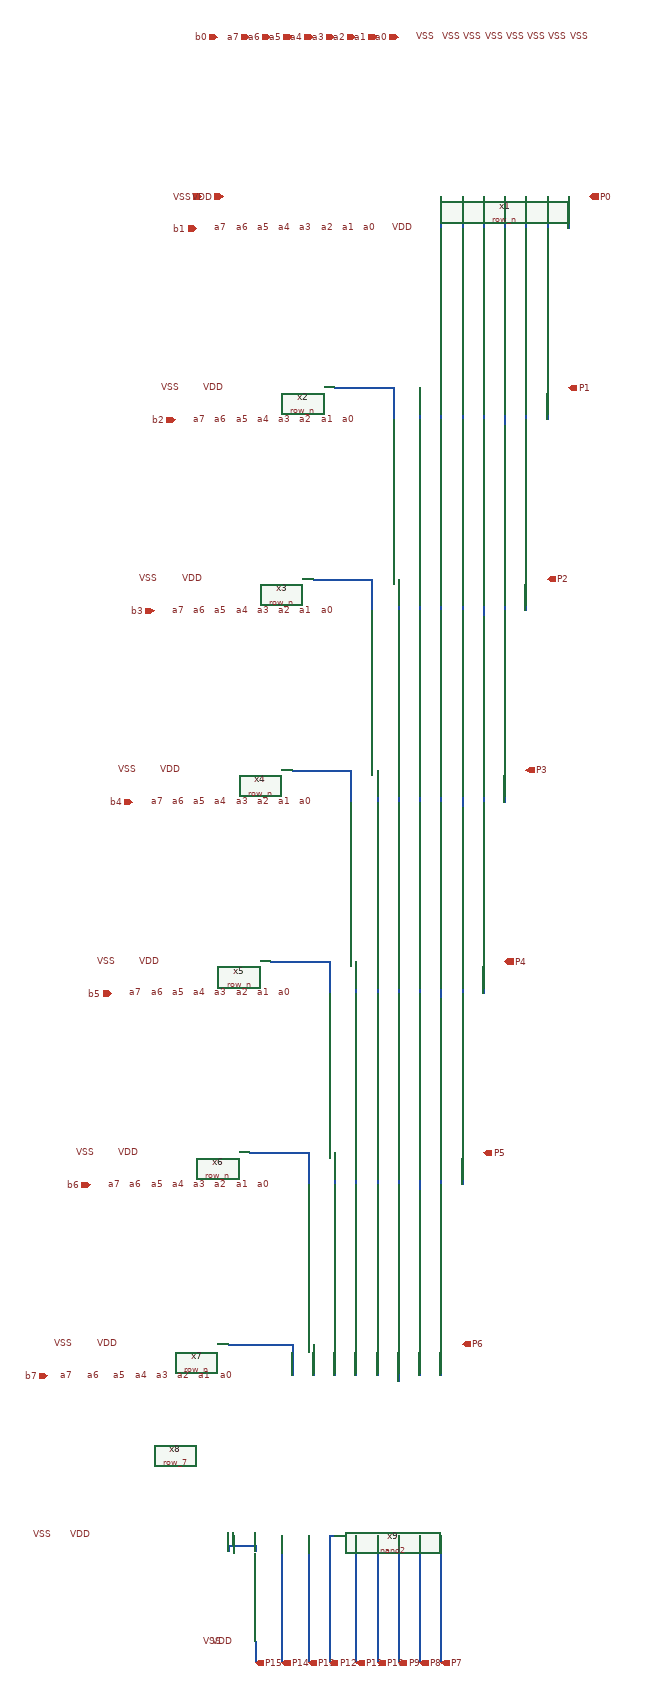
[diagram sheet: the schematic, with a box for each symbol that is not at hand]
v {xschem version=3.4.8RC file_version=1.3}
G {}
K {}
V {}
S {}
F {}
E {}
N 560 -280 560 -250 {lab=#net1}
N 520 -280 520 -250 {lab=#net2}
N 480 -280 480 -220 {lab=#net3}
N 440 -280 440 -250 {lab=#net4}
N 400 -280 400 -250 {lab=#net5}
N 360 -280 360 -250 {lab=#net6}
N 320 -280 320 -250 {lab=#net7}
N 320 -250 320 -220 {lab=#net7}
N 360 -250 360 -220 {lab=#net6}
N 400 -250 400 -220 {lab=#net5}
N 440 -250 440 -220 {lab=#net4}
N 520 -250 520 -220 {lab=#net2}
N 520 80 520 140 {lab=#net8}
N 480 80 480 140 {lab=#net9}
N 440 80 440 150 {lab=#net10}
N 400 80 400 140 {lab=#net11}
N 360 80 360 140 {lab=#net12}
N 320 80 320 140 {lab=#net13}
N 280 80 280 140 {lab=#net14}
N 120 80 230 80 {lab=#net15}
N 230 80 230 140 {lab=#net15}
N 480 440 480 500 {lab=#net16}
N 440 440 440 500 {lab=#net17}
N 400 440 400 510 {lab=#net18}
N 360 440 360 500 {lab=#net19}
N 320 440 320 500 {lab=#net20}
N 280 440 280 500 {lab=#net21}
N 240 440 240 500 {lab=#net22}
N 190 440 190 500 {lab=#net23}
N 80 440 190 440 {lab=#net23}
N 440 800 440 860 {lab=#net24}
N 400 800 400 860 {lab=#net25}
N 360 800 360 870 {lab=#net26}
N 320 800 320 860 {lab=#net27}
N 280 800 280 860 {lab=#net28}
N 240 800 240 860 {lab=#net29}
N 200 800 200 860 {lab=#net30}
N 150 800 150 860 {lab=#net31}
N 40 800 150 800 {lab=#net31}
N 560 -250 560 -220 {lab=#net1}
N 400 1160 400 1220 {lab=#net32}
N 360 1160 360 1220 {lab=#net33}
N 320 1160 320 1230 {lab=#net34}
N 280 1160 280 1220 {lab=#net35}
N 240 1160 240 1220 {lab=#net36}
N 200 1160 200 1220 {lab=#net37}
N 160 1160 160 1220 {lab=#net38}
N 110 1160 110 1220 {lab=#net39}
N -0 1160 110 1160 {lab=#net39}
N 360 1520 360 1580 {lab=#net40}
N 320 1520 320 1580 {lab=#net41}
N 280 1520 280 1590 {lab=#net42}
N 240 1520 240 1580 {lab=#net43}
N 200 1520 200 1580 {lab=#net44}
N 160 1520 160 1580 {lab=#net45}
N 120 1520 120 1580 {lab=#net46}
N 70 1520 70 1580 {lab=#net47}
N -40 1520 70 1520 {lab=#net47}
N 320 1880 320 1940 {lab=#net48}
N 280 1880 280 1940 {lab=#net49}
N 240 1880 240 1950 {lab=#net50}
N 200 1880 200 1940 {lab=#net51}
N 160 1880 160 1940 {lab=#net52}
N 120 1880 120 1940 {lab=#net53}
N 80 1880 80 1940 {lab=#net54}
N 40 1880 40 1940 {lab=#net55}
N -80 1880 40 1880 {lab=#net55}
N 20 2240 20 2480 {lab=P14}
N 70 2240 70 2480 {lab=P13}
N 110 2240 110 2480 {lab=P12}
N 110 2240 120 2240 {lab=P12}
N 160 2240 160 2480 {lab=P11}
N 200 2240 200 2480 {lab=P10}
N 240 2240 240 2480 {lab=P9}
N 280 2240 280 2480 {lab=P8}
N 320 2240 320 2480 {lab=P7}
N -30 2440 -30 2480 {lab=P15}
N -80 2260 -80 2270 {lab=#net56}
N -80 2260 -30 2260 {lab=#net56}
N -30 2260 -30 2270 {lab=#net56}
N -70 2240 -70 2260 {lab=#net56}
C {row_n.sym} 300 -430 1 0 {name=x1}
C {row_n.sym} 260 -70 1 0 {name=x2}
C {row_n.sym} 220 290 1 0 {name=x3}
C {row_n.sym} 180 650 1 0 {name=x4}
C {row_n.sym} 140 1010 1 0 {name=x5}
C {row_n.sym} 100 1370 1 0 {name=x6}
C {row_n.sym} 60 1730 1 0 {name=x7}
C {row_7.sym} -180 2090 1 0 {name=x8}
C {ipin.sym} 120 -580 1 0 {name=p1 lab=a3}
C {ipin.sym} 240 -580 1 0 {name=p2 lab=a0}
C {ipin.sym} 160 -580 1 0 {name=p3 lab=a2}
C {ipin.sym} 200 -580 1 0 {name=p4 lab=a1}
C {ipin.sym} 80 -580 1 0 {name=p5 lab=a4}
C {ipin.sym} 40 -580 1 0 {name=p6 lab=a5}
C {ipin.sym} 0 -580 1 0 {name=p7 lab=a6}
C {ipin.sym} -40 -580 1 0 {name=p8 lab=a7}
C {lab_pin.sym} 200 -220 1 0 {name=p9 sig_type=std_logic lab=a0}
C {lab_pin.sym} 160 -220 1 0 {name=p10 sig_type=std_logic lab=a1}
C {lab_pin.sym} 120 -220 1 0 {name=p11 sig_type=std_logic lab=a2}
C {lab_pin.sym} 80 -220 1 0 {name=p12 sig_type=std_logic lab=a3}
C {lab_pin.sym} 40 -220 1 0 {name=p13 sig_type=std_logic lab=a4}
C {lab_pin.sym} 0 -220 1 0 {name=p14 sig_type=std_logic lab=a5}
C {lab_pin.sym} -40 -220 1 0 {name=p15 sig_type=std_logic lab=a6}
C {lab_pin.sym} -80 -220 1 0 {name=p16 sig_type=std_logic lab=a7}
C {ipin.sym} -100 -580 1 0 {name=p17 lab=b0}
C {opin.sym} 600 -280 1 0 {name=p18 lab=P0}
C {iopin.sym} -130 -280 2 0 {name=p27 lab=VSS}
C {iopin.sym} -90 -280 0 0 {name=p28 lab=VDD}
C {lab_pin.sym} -130 80 2 0 {name=p29 sig_type=std_logic lab=VDD}
C {lab_pin.sym} -170 80 0 0 {name=p30 sig_type=std_logic lab=VSS}
C {lab_pin.sym} 160 140 1 0 {name=p31 sig_type=std_logic lab=a0}
C {lab_pin.sym} 120 140 1 0 {name=p32 sig_type=std_logic lab=a1}
C {lab_pin.sym} 80 140 1 0 {name=p33 sig_type=std_logic lab=a2}
C {lab_pin.sym} 40 140 1 0 {name=p34 sig_type=std_logic lab=a3}
C {lab_pin.sym} 0 140 1 0 {name=p35 sig_type=std_logic lab=a4}
C {lab_pin.sym} -40 140 1 0 {name=p36 sig_type=std_logic lab=a5}
C {lab_pin.sym} -80 140 1 0 {name=p37 sig_type=std_logic lab=a6}
C {lab_pin.sym} -120 140 1 0 {name=p38 sig_type=std_logic lab=a7}
C {lab_pin.sym} 120 500 1 0 {name=p39 sig_type=std_logic lab=a0}
C {lab_pin.sym} 80 500 1 0 {name=p40 sig_type=std_logic lab=a1}
C {lab_pin.sym} 40 500 1 0 {name=p41 sig_type=std_logic lab=a2}
C {lab_pin.sym} 0 500 1 0 {name=p42 sig_type=std_logic lab=a3}
C {lab_pin.sym} -40 500 1 0 {name=p43 sig_type=std_logic lab=a4}
C {lab_pin.sym} -80 500 1 0 {name=p44 sig_type=std_logic lab=a5}
C {lab_pin.sym} -120 500 1 0 {name=p45 sig_type=std_logic lab=a6}
C {lab_pin.sym} -160 500 1 0 {name=p46 sig_type=std_logic lab=a7}
C {lab_pin.sym} 80 860 1 0 {name=p47 sig_type=std_logic lab=a0}
C {lab_pin.sym} 40 860 1 0 {name=p48 sig_type=std_logic lab=a1}
C {lab_pin.sym} 0 860 1 0 {name=p49 sig_type=std_logic lab=a2}
C {lab_pin.sym} -40 860 1 0 {name=p50 sig_type=std_logic lab=a3}
C {lab_pin.sym} -80 860 1 0 {name=p51 sig_type=std_logic lab=a4}
C {lab_pin.sym} -120 860 1 0 {name=p52 sig_type=std_logic lab=a5}
C {lab_pin.sym} -160 860 1 0 {name=p53 sig_type=std_logic lab=a6}
C {lab_pin.sym} -200 860 1 0 {name=p54 sig_type=std_logic lab=a7}
C {lab_pin.sym} 40 1220 1 0 {name=p55 sig_type=std_logic lab=a0}
C {lab_pin.sym} 0 1220 1 0 {name=p56 sig_type=std_logic lab=a1}
C {lab_pin.sym} -40 1220 1 0 {name=p57 sig_type=std_logic lab=a2}
C {lab_pin.sym} -80 1220 1 0 {name=p58 sig_type=std_logic lab=a3}
C {lab_pin.sym} -120 1220 1 0 {name=p59 sig_type=std_logic lab=a4}
C {lab_pin.sym} -160 1220 1 0 {name=p60 sig_type=std_logic lab=a5}
C {lab_pin.sym} -200 1220 1 0 {name=p61 sig_type=std_logic lab=a6}
C {lab_pin.sym} -240 1220 1 0 {name=p62 sig_type=std_logic lab=a7}
C {lab_pin.sym} 0 1580 1 0 {name=p63 sig_type=std_logic lab=a0}
C {lab_pin.sym} -40 1580 1 0 {name=p64 sig_type=std_logic lab=a1}
C {lab_pin.sym} -80 1580 1 0 {name=p65 sig_type=std_logic lab=a2}
C {lab_pin.sym} -120 1580 1 0 {name=p66 sig_type=std_logic lab=a3}
C {lab_pin.sym} -160 1580 1 0 {name=p67 sig_type=std_logic lab=a4}
C {lab_pin.sym} -200 1580 1 0 {name=p68 sig_type=std_logic lab=a5}
C {lab_pin.sym} -240 1580 1 0 {name=p69 sig_type=std_logic lab=a6}
C {lab_pin.sym} -280 1580 1 0 {name=p70 sig_type=std_logic lab=a7}
C {lab_pin.sym} -70 1940 1 0 {name=p71 sig_type=std_logic lab=a0}
C {lab_pin.sym} -110 1940 1 0 {name=p72 sig_type=std_logic lab=a1}
C {lab_pin.sym} -150 1940 1 0 {name=p73 sig_type=std_logic lab=a2}
C {lab_pin.sym} -190 1940 1 0 {name=p74 sig_type=std_logic lab=a3}
C {lab_pin.sym} -230 1940 1 0 {name=p75 sig_type=std_logic lab=a4}
C {lab_pin.sym} -270 1940 1 0 {name=p76 sig_type=std_logic lab=a5}
C {lab_pin.sym} -320 1940 1 0 {name=p77 sig_type=std_logic lab=a6}
C {lab_pin.sym} -370 1940 1 0 {name=p78 sig_type=std_logic lab=a7}
C {ipin.sym} -140 -220 1 0 {name=p79 lab=b1}
C {ipin.sym} -180 140 1 0 {name=p80 lab=b2}
C {ipin.sym} -220 500 1 0 {name=p81 lab=b3}
C {ipin.sym} -260 860 1 0 {name=p82 lab=b4}
C {ipin.sym} -300 1220 1 0 {name=p83 lab=b5}
C {ipin.sym} -340 1580 1 0 {name=p84 lab=b6}
C {ipin.sym} -420 1940 1 0 {name=p85 lab=b7}
C {lab_pin.sym} -170 440 2 0 {name=p86 sig_type=std_logic lab=VDD}
C {lab_pin.sym} -210 440 0 0 {name=p87 sig_type=std_logic lab=VSS}
C {lab_pin.sym} -210 800 2 0 {name=p88 sig_type=std_logic lab=VDD}
C {lab_pin.sym} -250 800 0 0 {name=p89 sig_type=std_logic lab=VSS}
C {lab_pin.sym} -250 1160 2 0 {name=p90 sig_type=std_logic lab=VDD}
C {lab_pin.sym} -290 1160 0 0 {name=p91 sig_type=std_logic lab=VSS}
C {lab_pin.sym} -290 1520 2 0 {name=p92 sig_type=std_logic lab=VDD}
C {lab_pin.sym} -330 1520 0 0 {name=p93 sig_type=std_logic lab=VSS}
C {lab_pin.sym} -330 1880 2 0 {name=p94 sig_type=std_logic lab=VDD}
C {lab_pin.sym} -370 1880 0 0 {name=p95 sig_type=std_logic lab=VSS}
C {lab_pin.sym} -380 2240 2 0 {name=p96 sig_type=std_logic lab=VDD}
C {lab_pin.sym} -410 2240 0 0 {name=p97 sig_type=std_logic lab=VSS}
C {lab_pin.sym} 270 -220 1 0 {name=p98 sig_type=std_logic lab=VDD}
C {opin.sym} 560 80 1 0 {name=p99 lab=P1}
C {opin.sym} 520 440 1 0 {name=p100 lab=P2}
C {opin.sym} 480 800 1 0 {name=p101 lab=P3}
C {opin.sym} 440 1160 1 0 {name=p102 lab=P4}
C {opin.sym} 400 1520 1 0 {name=p103 lab=P5}
C {opin.sym} 360 1880 1 0 {name=p104 lab=P6}
C {opin.sym} 20 2480 1 0 {name=p105 lab=P14}
C {lab_pin.sym} 600 -580 1 0 {name=p106 sig_type=std_logic lab=VSS}
C {lab_pin.sym} 560 -580 1 0 {name=p22 sig_type=std_logic lab=VSS}
C {lab_pin.sym} 520 -580 1 0 {name=p23 sig_type=std_logic lab=VSS}
C {lab_pin.sym} 480 -580 1 0 {name=p24 sig_type=std_logic lab=VSS}
C {lab_pin.sym} 440 -580 1 0 {name=p25 sig_type=std_logic lab=VSS}
C {lab_pin.sym} 400 -580 1 0 {name=p26 sig_type=std_logic lab=VSS}
C {lab_pin.sym} 360 -580 1 0 {name=p107 sig_type=std_logic lab=VSS}
C {lab_pin.sym} 310 -580 1 0 {name=p108 sig_type=std_logic lab=VSS}
C {opin.sym} 70 2480 1 0 {name=p20 lab=P13}
C {opin.sym} 110 2480 1 0 {name=p21 lab=P12}
C {opin.sym} 160 2480 1 0 {name=p109 lab=P11}
C {opin.sym} 200 2480 1 0 {name=p110 lab=P10}
C {opin.sym} 240 2480 1 0 {name=p111 lab=P9}
C {opin.sym} 280 2480 1 0 {name=p112 lab=P8}
C {opin.sym} 320 2480 1 0 {name=p113 lab=P7}
C {nand2.sym} -70 2290 1 0 {name=x9}
C {opin.sym} -30 2480 1 0 {name=p114 lab=P15}
C {lab_pin.sym} -70 2440 3 0 {name=p117 sig_type=std_logic lab=VDD}
C {lab_pin.sym} -90 2440 3 0 {name=p118 sig_type=std_logic lab=VSS}
